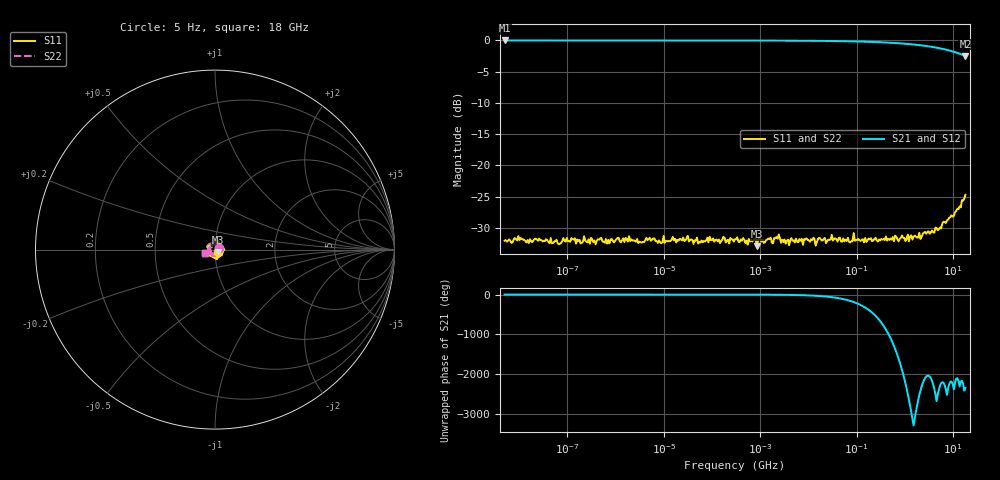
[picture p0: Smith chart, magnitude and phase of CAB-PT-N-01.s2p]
! CAL-ELEKTRA — DATOS SINTÉTICOS DE EJEMPLO: no son una medida real.
! Cable simulado CAB-PT-N-01: 1.5 m, 5 Hz – 18 GHz
# HZ S RI R 50
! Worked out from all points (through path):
!   401 points, 5 Hz to 18 GHz, reference 50 ohm
!   highest |S21| = 0.00 dB at 5 Hz (marker M1); lowest = -2.5 dB at 18 GHz (marker M2)
!   lowest |S11| = -32.9 dB at 853.2 kHz (marker M3), VSWR 1.05, Z = 51.7 - j1.51 ohm
!   |S11| at or under -10 dB: start of sweep to end of sweep
!   |S22| runs from -32.9 to -24.7 dB; largest |S21 - S12| = 0
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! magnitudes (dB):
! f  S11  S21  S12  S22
! 5 Hz  -32.0  0.0  0.0  -32.0
! 10.8 Hz  -31.6  0.0  0.0  -31.6
! 70.1 Hz  -32.5  0.0  0.0  -32.5
! 87.36 Hz  -32.0  0.0  0.0  -32.0
! 199.4 Hz  -32.4  0.0  0.0  -32.4
! 1.8 kHz  -32.2  0.0  0.0  -32.2
! 3.297 kHz  -32.3  0.0  0.0  -32.3
! 5.715 kHz  -31.8  0.0  0.0  -31.8
! 7.949 kHz  -32.0  0.0  0.0  -32.0
! 28.17 kHz  -32.0  0.0  0.0  -32.0
! 57.6 kHz  -32.3  0.0  0.0  -32.3
! 300 kHz  -31.8  0.0  0.0  -31.8
! 853.2 kHz  -32.9  0.0  0.0  -32.9
! 1.947 MHz  -31.6  0.0  0.0  -31.6
! 2.174 MHz  -31.5  0.0  0.0  -31.5
! 3.024 MHz  -32.3  0.0  0.0  -32.3
! 11.96 MHz  -31.9  -0.1  -0.1  -31.9
! 477 MHz  -31.9  -0.4  -0.4  -31.9
! 1.994 GHz  -30.8  -0.7  -0.7  -30.8
! 5.079 GHz  -30.2  -1.2  -1.2  -30.2
! 10.97 GHz  -27.5  -1.9  -1.9  -27.5
! 18 GHz  -24.7  -2.5  -2.5  -24.7
